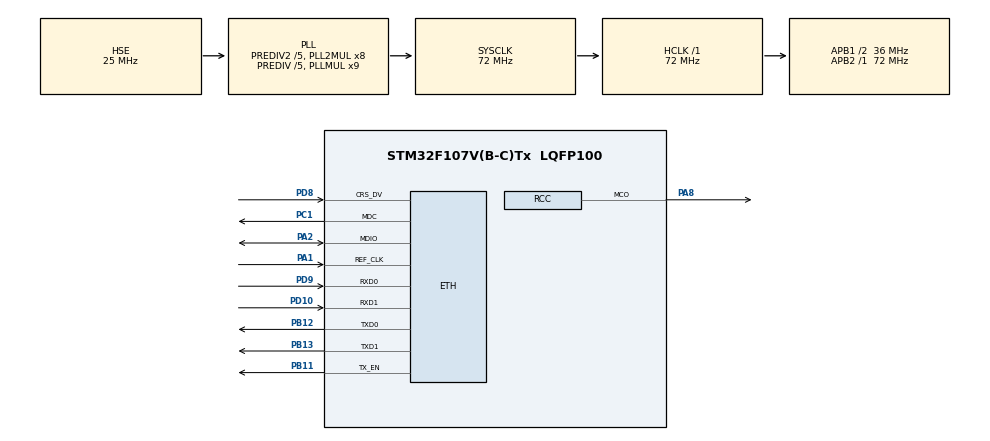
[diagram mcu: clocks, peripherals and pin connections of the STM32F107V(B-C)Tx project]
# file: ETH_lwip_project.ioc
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ETH.MediaInterface=ETH_MEDIA_INTERFACE_RMII
LWIP.GATEWAY_ADDRESS=192.168.001.001
LWIP.IP_ADDRESS=192.168.001.252
LWIP.LWIP_DHCP=0
LWIP.NETMASK_ADDRESS=255.255.255.000
LWIP.Version=v2.0.0_Cube
Mcu.Family=STM32F1
Mcu.Name=STM32F107V(B-C)Tx
Mcu.Package=LQFP100
NVIC.ETH_IRQn=true\:0\:0\:false\:false\:true\:true
NVIC.PriorityGroup=NVIC_PRIORITYGROUP_4
OSC_IN.Mode=HSE-External-Oscillator
OSC_IN.Signal=RCC_OSC_IN
OSC_OUT.Mode=HSE-External-Oscillator
OSC_OUT.Signal=RCC_OSC_OUT
PA1.Mode=RMII
PA1.Signal=ETH_REF_CLK
PA13.Mode=Serial_Wire
PA13.Signal=SYS_JTMS-SWDIO
PA14.Mode=Serial_Wire
PA14.Signal=SYS_JTCK-SWCLK
PA2.Mode=RMII
PA2.Signal=ETH_MDIO
PA8.GPIO_Speed=GPIO_SPEED_FREQ_HIGH
PA8.Mode=Clock-out
PA8.Signal=RCC_MCO
PB11.Mode=RMII
PB11.Signal=ETH_TX_EN
PB12.Mode=RMII
PB12.Signal=ETH_TXD0
PB13.Mode=RMII
PB13.Signal=ETH_TXD1
PC1.Mode=RMII
PC1.Signal=ETH_MDC
PD10.Mode=RMII
PD10.Signal=ETH_RXD1
PD8.Mode=RMII
PD8.Signal=ETH_CRS_DV
PD9.Mode=RMII
PD9.Signal=ETH_RXD0
ProjectManager.HeapSize=0x200
ProjectManager.StackSize=0x400
ProjectManager.TargetToolchain=MDK-ARM V5
RCC.AHBFreq_Value=72000000
RCC.APB1CLKDivider=RCC_HCLK_DIV2
RCC.APB1Freq_Value=36000000
RCC.APB1TimFreq_Value=72000000
RCC.APB2Freq_Value=72000000
RCC.APB2TimFreq_Value=72000000
RCC.HCLKFreq_Value=72000000
RCC.HSEDivPLL=RCC_HSE_PREDIV_DIV5
RCC.HSE_VALUE=25000000
RCC.PLL3Mul=RCC_PLLI2S_MUL10
RCC.PLLMUL=RCC_PLL_MUL9
RCC.PLLSourceVirtual=RCC_PLLSOURCE_HSE
RCC.Prediv1Source=RCC_PREDIV1_SOURCE_PLL2
RCC.Prediv2=RCC_HSE_PREDIV2_DIV5
RCC.RCC_MCOSource=RCC_MCO1SOURCE_PLL3CLK
RCC.SYSCLKFreq_VALUE=72000000
RCC.SYSCLKSource=RCC_SYSCLKSOURCE_PLLCLK
RCC.USBFreq_Value=48000000
VP_LWIP_VS_Enabled.Mode=Enabled
board=ETH_lwip_project

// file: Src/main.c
/**
  ******************************************************************************
  * File Name          : main.c
  * Description        : Main program body
  ******************************************************************************
  * This notice applies to any and all portions of this file
  * that are not between comment pairs USER CODE BEGIN and
  * USER CODE END. Other portions of this file, whether
  * inserted by the user or by software development tools
  * are owned by their respective copyright owners.
  *
  * Copyright (c) 2018 STMicroelectronics International N.V.
  * All rights reserved.
  *
  * Redistribution and use in source and binary forms, with or without
  * modification, are permitted, provided that the following conditions are met:
  *
  * 1. Redistribution of source code must retain the above copyright notice,
  *    this list of conditions and the following disclaimer.
  * 2. Redistributions in binary form must reproduce the above copyright notice,
  *    this list of conditions and the following disclaimer in the documentation
  *    and/or other materials provided with the distribution.
  * 3. Neither the name of STMicroelectronics nor the names of other
  *    contributors to this software may be used to endorse or promote products
  *    derived from this software without specific written permission.
  * 4. This software, including modifications and/or derivative works of this
  *    software, must execute solely and exclusively on microcontroller or
  *    microprocessor devices manufactured by or for STMicroelectronics.
  * 5. Redistribution and use of this software other than as permitted under
  *    this license is void and will automatically terminate your rights under
  *    this license.
  *
  * THIS SOFTWARE IS PROVIDED BY STMICROELECTRONICS AND CONTRIBUTORS "AS IS"
  * AND ANY EXPRESS, IMPLIED OR STATUTORY WARRANTIES, INCLUDING, BUT NOT
  * LIMITED TO, THE IMPLIED WARRANTIES OF MERCHANTABILITY, FITNESS FOR A
  * PARTICULAR PURPOSE AND NON-INFRINGEMENT OF THIRD PARTY INTELLECTUAL PROPERTY
  * RIGHTS ARE DISCLAIMED TO THE FULLEST EXTENT PERMITTED BY LAW. IN NO EVENT
  * SHALL STMICROELECTRONICS OR CONTRIBUTORS BE LIABLE FOR ANY DIRECT, INDIRECT,
  * INCIDENTAL, SPECIAL, EXEMPLARY, OR CONSEQUENTIAL DAMAGES (INCLUDING, BUT NOT
  * LIMITED TO, PROCUREMENT OF SUBSTITUTE GOODS OR SERVICES; LOSS OF USE, DATA,
  * OR PROFITS; OR BUSINESS INTERRUPTION) HOWEVER CAUSED AND ON ANY THEORY OF
  * LIABILITY, WHETHER IN CONTRACT, STRICT LIABILITY, OR TORT (INCLUDING
  * NEGLIGENCE OR OTHERWISE) ARISING IN ANY WAY OUT OF THE USE OF THIS SOFTWARE,
  * EVEN IF ADVISED OF THE POSSIBILITY OF SUCH DAMAGE.
  *
  ******************************************************************************
  */

#include "main.h"
#include "stm32f1xx_hal.h"
#include "lwip.h"

/* USER CODE BEGIN Includes */
#include "udp_echoserver.h"
#include "app_ethernet.h"
/* USER CODE END Includes */

/* USER CODE BEGIN PV */
/* Private variables ---------------------------------------------------------*/

/* USER CODE END PV */

void SystemClock_Config(void);
static void MX_GPIO_Init(void);

/* USER CODE BEGIN PFP */
/* Private function prototypes -----------------------------------------------*/

/* USER CODE END PFP */

int main(void)
{

  /* MCU Configuration----------------------------------------------------------*/

  /* Reset of all peripherals, Initializes the Flash interface and the Systick. */
  HAL_Init();

  /* Configure the system clock */
  SystemClock_Config();

  /* Initialize all configured peripherals */
  MX_GPIO_Init();
  MX_LWIP_Init();

  /* USER CODE BEGIN 2 */
	udp_echoserver_init();
	User_notification(&gnetif);   //用来检测网络有没有连通；
  /* USER CODE END 2 */

  /* Infinite loop */
  while (1)
  {

  /* USER CODE BEGIN 3 */
		MX_LWIP_Process();
  }
  /* USER CODE END 3 */

}

/** System Clock Configuration
*/
void SystemClock_Config(void)
{

  RCC_OscInitTypeDef RCC_OscInitStruct;
  RCC_ClkInitTypeDef RCC_ClkInitStruct;

    /**Initializes the CPU, AHB and APB busses clocks
    */
  RCC_OscInitStruct.OscillatorType = RCC_OSCILLATORTYPE_HSE;
  RCC_OscInitStruct.HSEState = RCC_HSE_ON;
  RCC_OscInitStruct.HSEPredivValue = RCC_HSE_PREDIV_DIV5;
  RCC_OscInitStruct.HSIState = RCC_HSI_ON;
  RCC_OscInitStruct.Prediv1Source = RCC_PREDIV1_SOURCE_PLL2;
  RCC_OscInitStruct.PLL.PLLState = RCC_PLL_ON;
  RCC_OscInitStruct.PLL.PLLSource = RCC_PLLSOURCE_HSE;
  RCC_OscInitStruct.PLL.PLLMUL = RCC_PLL_MUL9;
  RCC_OscInitStruct.PLL2.PLL2State = RCC_PLL2_ON;
  RCC_OscInitStruct.PLL2.PLL2MUL = RCC_PLL2_MUL8;
  RCC_OscInitStruct.PLL2.HSEPrediv2Value = RCC_HSE_PREDIV2_DIV5;
  if (HAL_RCC_OscConfig(&RCC_OscInitStruct) != HAL_OK)
  {
    _Error_Handler(__FILE__, __LINE__);
  }

    /**Initializes the CPU, AHB and APB busses clocks
    */
  RCC_ClkInitStruct.ClockType = RCC_CLOCKTYPE_HCLK|RCC_CLOCKTYPE_SYSCLK
                              |RCC_CLOCKTYPE_PCLK1|RCC_CLOCKTYPE_PCLK2;
  RCC_ClkInitStruct.SYSCLKSource = RCC_SYSCLKSOURCE_PLLCLK;
  RCC_ClkInitStruct.AHBCLKDivider = RCC_SYSCLK_DIV1;
  RCC_ClkInitStruct.APB1CLKDivider = RCC_HCLK_DIV2;
  RCC_ClkInitStruct.APB2CLKDivider = RCC_HCLK_DIV1;

  if (HAL_RCC_ClockConfig(&RCC_ClkInitStruct, FLASH_LATENCY_2) != HAL_OK)
  {
    _Error_Handler(__FILE__, __LINE__);
  }

  HAL_RCC_MCOConfig(RCC_MCO, RCC_MCO1SOURCE_PLL3CLK, RCC_MCODIV_1);

    /**Configure the Systick interrupt time
    */
  HAL_SYSTICK_Config(HAL_RCC_GetHCLKFreq()/1000);

    /**Configure the Systick
    */
  HAL_SYSTICK_CLKSourceConfig(SYSTICK_CLKSOURCE_HCLK);

    /**Configure the Systick interrupt time
    */
  __HAL_RCC_HSE_PREDIV2_CONFIG(RCC_HSE_PREDIV2_DIV5);

    /**Configure the Systick interrupt time
    */
  __HAL_RCC_PLLI2S_CONFIG(RCC_PLLI2S_MUL10);

    /**Configure the Systick interrupt time
    */
  __HAL_RCC_PLLI2S_ENABLE();

  /* SysTick_IRQn interrupt configuration */
  HAL_NVIC_SetPriority(SysTick_IRQn, 0, 0);
}

/** Configure pins as
        * Analog
        * Input
        * Output
        * EVENT_OUT
        * EXTI
     PA8   ------> RCC_MCO
*/
static void MX_GPIO_Init(void)
{

  GPIO_InitTypeDef GPIO_InitStruct;

  /* GPIO Ports Clock Enable */
  __HAL_RCC_GPIOC_CLK_ENABLE();
  __HAL_RCC_GPIOA_CLK_ENABLE();
  __HAL_RCC_GPIOE_CLK_ENABLE();
  __HAL_RCC_GPIOB_CLK_ENABLE();
  __HAL_RCC_GPIOD_CLK_ENABLE();

  /*Configure GPIO pin Output Level */
  HAL_GPIO_WritePin(GPIOE, LED1_Pin|LED2_Pin|LED3_Pin, GPIO_PIN_SET);

  /*Configure GPIO pins : LED1_Pin LED2_Pin LED3_Pin */
  GPIO_InitStruct.Pin = LED1_Pin|LED2_Pin|LED3_Pin;
  GPIO_InitStruct.Mode = GPIO_MODE_OUTPUT_PP;
  GPIO_InitStruct.Speed = GPIO_SPEED_FREQ_LOW;
  HAL_GPIO_Init(GPIOE, &GPIO_InitStruct);

  /*Configure GPIO pin : PA8 */
  GPIO_InitStruct.Pin = GPIO_PIN_8;
  GPIO_InitStruct.Mode = GPIO_MODE_AF_PP;
  GPIO_InitStruct.Speed = GPIO_SPEED_FREQ_HIGH;
  HAL_GPIO_Init(GPIOA, &GPIO_InitStruct);

}

void _Error_Handler(char * file, int line)
{
  while(1)
  {
  }
}

/************************ (C) COPYRIGHT STMicroelectronics *****END OF FILE****/
